VERSION 5.7 ;
  NAMESCASESENSITIVE ON ;
  NOWIREEXTENSIONATPIN ON ;
  DIVIDERCHAR "/" ;
  BUSBITCHARS "[]" ;
UNITS
  DATABASE MICRONS 200 ;
END UNITS

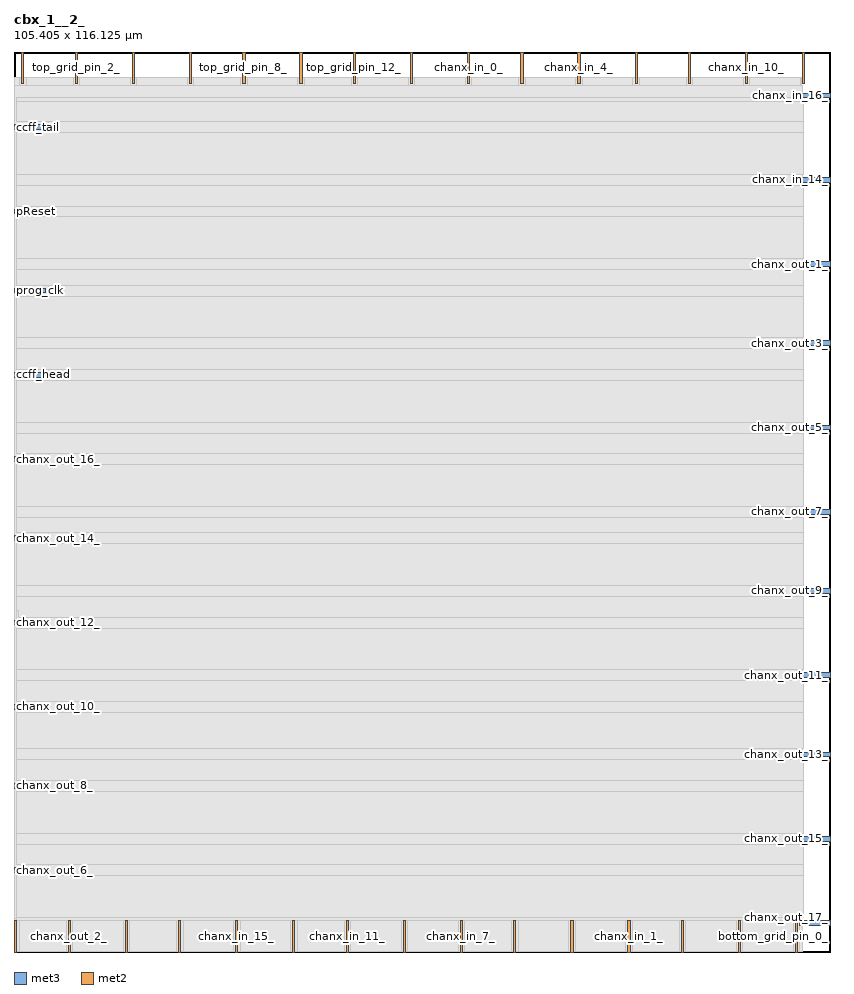
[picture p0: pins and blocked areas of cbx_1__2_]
MACRO cbx_1__2_
  CLASS BLOCK ;
  FOREIGN cbx_1__2_ ;
  ORIGIN 0.000 0.000 ;
  SIZE 105.405 BY 116.125 ;
  PIN chanx_out_8_
    DIRECTION OUTPUT TRISTATE ;
    PORT
      LAYER met3 ;
        RECT 0.000 21.120 4.000 21.720 ;
    END
  END chanx_out_8_
  PIN top_grid_pin_0_
    DIRECTION OUTPUT TRISTATE ;
    PORT
      LAYER met2 ;
        RECT 1.010 112.125 1.290 116.125 ;
    END
  END top_grid_pin_0_
  PIN pReset
    DIRECTION INPUT ;
    PORT
      LAYER met3 ;
        RECT 0.000 95.240 4.000 95.840 ;
    END
  END pReset
  PIN chanx_out_16_
    DIRECTION OUTPUT TRISTATE ;
    PORT
      LAYER met3 ;
        RECT 0.000 63.280 4.000 63.880 ;
    END
  END chanx_out_16_
  PIN top_grid_pin_12_
    DIRECTION OUTPUT TRISTATE ;
    PORT
      LAYER met2 ;
        RECT 43.790 112.125 44.070 116.125 ;
    END
  END top_grid_pin_12_
  PIN chanx_in_5_
    DIRECTION INPUT ;
    PORT
      LAYER met2 ;
        RECT 64.490 0.000 64.770 4.000 ;
    END
  END chanx_in_5_
  PIN chanx_in_1_
    DIRECTION INPUT ;
    PORT
      LAYER met2 ;
        RECT 79.210 0.000 79.490 4.000 ;
    END
  END chanx_in_1_
  PIN top_grid_pin_8_
    DIRECTION OUTPUT TRISTATE ;
    PORT
      LAYER met2 ;
        RECT 29.530 112.125 29.810 116.125 ;
    END
  END top_grid_pin_8_
  PIN chanx_out_10_
    DIRECTION OUTPUT TRISTATE ;
    PORT
      LAYER met3 ;
        RECT 0.000 31.320 4.000 31.920 ;
    END
  END chanx_out_10_
  PIN chanx_in_10_
    DIRECTION INPUT ;
    PORT
      LAYER met2 ;
        RECT 94.390 112.125 94.670 116.125 ;
    END
  END chanx_in_10_
  PIN chanx_out_3_
    DIRECTION OUTPUT TRISTATE ;
    PORT
      LAYER met3 ;
        RECT 101.405 78.240 105.405 78.840 ;
    END
  END chanx_out_3_
  PIN prog_clk
    DIRECTION INPUT ;
    PORT
      LAYER met3 ;
        RECT 0.000 85.040 4.000 85.640 ;
    END
  END prog_clk
  PIN bottom_grid_pin_8_
    DIRECTION OUTPUT TRISTATE ;
    PORT
      LAYER met2 ;
        RECT 86.110 0.000 86.390 4.000 ;
    END
  END bottom_grid_pin_8_
  PIN ccff_tail
    DIRECTION OUTPUT TRISTATE ;
    PORT
      LAYER met3 ;
        RECT 0.000 106.120 4.000 106.720 ;
    END
  END ccff_tail
  PIN top_grid_pin_14_
    DIRECTION OUTPUT TRISTATE ;
    PORT
      LAYER met2 ;
        RECT 51.150 112.125 51.430 116.125 ;
    END
  END top_grid_pin_14_
  PIN chanx_out_0_
    DIRECTION OUTPUT TRISTATE ;
    PORT
      LAYER met2 ;
        RECT 14.350 0.000 14.630 4.000 ;
    END
  END chanx_out_0_
  PIN chanx_out_13_
    DIRECTION OUTPUT TRISTATE ;
    PORT
      LAYER met3 ;
        RECT 101.405 25.200 105.405 25.800 ;
    END
  END chanx_out_13_
  PIN chanx_out_12_
    DIRECTION OUTPUT TRISTATE ;
    PORT
      LAYER met3 ;
        RECT 0.000 42.200 4.000 42.800 ;
    END
  END chanx_out_12_
  PIN chanx_out_9_
    DIRECTION OUTPUT TRISTATE ;
    PORT
      LAYER met3 ;
        RECT 101.405 46.280 105.405 46.880 ;
    END
  END chanx_out_9_
  PIN chanx_in_16_
    DIRECTION INPUT ;
    PORT
      LAYER met3 ;
        RECT 101.405 110.200 105.405 110.800 ;
    END
  END chanx_in_16_
  PIN chanx_out_15_
    DIRECTION OUTPUT TRISTATE ;
    PORT
      LAYER met3 ;
        RECT 101.405 14.320 105.405 14.920 ;
    END
  END chanx_out_15_
  PIN top_grid_pin_2_
    DIRECTION OUTPUT TRISTATE ;
    PORT
      LAYER met2 ;
        RECT 7.910 112.125 8.190 116.125 ;
    END
  END top_grid_pin_2_
  PIN chanx_in_4_
    DIRECTION INPUT ;
    PORT
      LAYER met2 ;
        RECT 72.770 112.125 73.050 116.125 ;
    END
  END chanx_in_4_
  PIN chanx_out_17_
    DIRECTION OUTPUT TRISTATE ;
    PORT
      LAYER met3 ;
        RECT 101.405 3.440 105.405 4.040 ;
    END
  END chanx_out_17_
  PIN top_grid_pin_10_
    DIRECTION OUTPUT TRISTATE ;
    PORT
      LAYER met2 ;
        RECT 36.890 112.125 37.170 116.125 ;
    END
  END top_grid_pin_10_
  PIN chanx_in_13_
    DIRECTION INPUT ;
    PORT
      LAYER met2 ;
        RECT 35.970 0.000 36.250 4.000 ;
    END
  END chanx_in_13_
  PIN top_grid_pin_6_
    DIRECTION OUTPUT TRISTATE ;
    PORT
      LAYER met2 ;
        RECT 22.630 112.125 22.910 116.125 ;
    END
  END top_grid_pin_6_
  PIN bottom_grid_pin_0_
    DIRECTION OUTPUT TRISTATE ;
    PORT
      LAYER met2 ;
        RECT 100.830 0.000 101.110 4.000 ;
    END
  END bottom_grid_pin_0_
  PIN chanx_in_8_
    DIRECTION INPUT ;
    PORT
      LAYER met2 ;
        RECT 87.030 112.125 87.310 116.125 ;
    END
  END chanx_in_8_
  PIN ccff_head
    DIRECTION INPUT ;
    PORT
      LAYER met3 ;
        RECT 0.000 74.160 4.000 74.760 ;
    END
  END ccff_head
  PIN chanx_in_9_
    DIRECTION INPUT ;
    PORT
      LAYER met2 ;
        RECT 50.230 0.000 50.510 4.000 ;
    END
  END chanx_in_9_
  PIN chanx_out_1_
    DIRECTION OUTPUT TRISTATE ;
    PORT
      LAYER met3 ;
        RECT 101.405 88.440 105.405 89.040 ;
    END
  END chanx_out_1_
  PIN chanx_in_6_
    DIRECTION INPUT ;
    PORT
      LAYER met2 ;
        RECT 80.130 112.125 80.410 116.125 ;
    END
  END chanx_in_6_
  PIN chanx_in_12_
    DIRECTION INPUT ;
    PORT
      LAYER met2 ;
        RECT 101.750 112.125 102.030 116.125 ;
    END
  END chanx_in_12_
  PIN chanx_out_11_
    DIRECTION OUTPUT TRISTATE ;
    PORT
      LAYER met3 ;
        RECT 101.405 35.400 105.405 36.000 ;
    END
  END chanx_out_11_
  PIN chanx_in_15_
    DIRECTION INPUT ;
    PORT
      LAYER met2 ;
        RECT 28.610 0.000 28.890 4.000 ;
    END
  END chanx_in_15_
  PIN chanx_in_17_
    DIRECTION INPUT ;
    PORT
      LAYER met2 ;
        RECT 21.250 0.000 21.530 4.000 ;
    END
  END chanx_in_17_
  PIN bottom_grid_pin_4_
    DIRECTION OUTPUT TRISTATE ;
    PORT
      LAYER met2 ;
        RECT 93.470 0.000 93.750 4.000 ;
    END
  END bottom_grid_pin_4_
  PIN chanx_in_3_
    DIRECTION INPUT ;
    PORT
      LAYER met2 ;
        RECT 71.850 0.000 72.130 4.000 ;
    END
  END chanx_in_3_
  PIN chanx_in_7_
    DIRECTION INPUT ;
    PORT
      LAYER met2 ;
        RECT 57.590 0.000 57.870 4.000 ;
    END
  END chanx_in_7_
  PIN chanx_in_11_
    DIRECTION INPUT ;
    PORT
      LAYER met2 ;
        RECT 42.870 0.000 43.150 4.000 ;
    END
  END chanx_in_11_
  PIN chanx_out_14_
    DIRECTION OUTPUT TRISTATE ;
    PORT
      LAYER met3 ;
        RECT 0.000 53.080 4.000 53.680 ;
    END
  END chanx_out_14_
  PIN chanx_out_2_
    DIRECTION OUTPUT TRISTATE ;
    PORT
      LAYER met2 ;
        RECT 6.990 0.000 7.270 4.000 ;
    END
  END chanx_out_2_
  PIN chanx_in_0_
    DIRECTION INPUT ;
    PORT
      LAYER met2 ;
        RECT 58.510 112.125 58.790 116.125 ;
    END
  END chanx_in_0_
  PIN chanx_out_5_
    DIRECTION OUTPUT TRISTATE ;
    PORT
      LAYER met3 ;
        RECT 101.405 67.360 105.405 67.960 ;
    END
  END chanx_out_5_
  PIN chanx_out_6_
    DIRECTION OUTPUT TRISTATE ;
    PORT
      LAYER met3 ;
        RECT 0.000 10.240 4.000 10.840 ;
    END
  END chanx_out_6_
  PIN top_grid_pin_4_
    DIRECTION OUTPUT TRISTATE ;
    PORT
      LAYER met2 ;
        RECT 15.270 112.125 15.550 116.125 ;
    END
  END top_grid_pin_4_
  PIN chanx_in_2_
    DIRECTION INPUT ;
    PORT
      LAYER met2 ;
        RECT 65.410 112.125 65.690 116.125 ;
    END
  END chanx_in_2_
  PIN chanx_in_14_
    DIRECTION INPUT ;
    PORT
      LAYER met3 ;
        RECT 101.405 99.320 105.405 99.920 ;
    END
  END chanx_in_14_
  PIN chanx_out_7_
    DIRECTION OUTPUT TRISTATE ;
    PORT
      LAYER met3 ;
        RECT 101.405 56.480 105.405 57.080 ;
    END
  END chanx_out_7_
  PIN chanx_out_4_
    DIRECTION OUTPUT TRISTATE ;
    PORT
      LAYER met2 ;
        RECT 0.090 0.000 0.370 4.000 ;
    END
  END chanx_out_4_
  OBS
      LAYER li1 ;
        RECT 5.520 10.795 99.820 103.445 ;
      LAYER met1 ;
        RECT 0.070 0.040 101.590 112.840 ;
      LAYER met2 ;
        RECT 0.090 111.845 0.730 112.870 ;
        RECT 1.570 111.845 7.630 112.870 ;
        RECT 8.470 111.845 14.990 112.870 ;
        RECT 15.830 111.845 22.350 112.870 ;
        RECT 23.190 111.845 29.250 112.870 ;
        RECT 30.090 111.845 36.610 112.870 ;
        RECT 37.450 111.845 43.510 112.870 ;
        RECT 44.350 111.845 50.870 112.870 ;
        RECT 51.710 111.845 58.230 112.870 ;
        RECT 59.070 111.845 65.130 112.870 ;
        RECT 65.970 111.845 72.490 112.870 ;
        RECT 73.330 111.845 79.850 112.870 ;
        RECT 80.690 111.845 86.750 112.870 ;
        RECT 87.590 111.845 94.110 112.870 ;
        RECT 94.950 111.845 101.470 112.870 ;
        RECT 0.090 4.280 101.750 111.845 ;
        RECT 0.650 0.010 6.710 4.280 ;
        RECT 7.550 0.010 14.070 4.280 ;
        RECT 14.910 0.010 20.970 4.280 ;
        RECT 21.810 0.010 28.330 4.280 ;
        RECT 29.170 0.010 35.690 4.280 ;
        RECT 36.530 0.010 42.590 4.280 ;
        RECT 43.430 0.010 49.950 4.280 ;
        RECT 50.790 0.010 57.310 4.280 ;
        RECT 58.150 0.010 64.210 4.280 ;
        RECT 65.050 0.010 71.570 4.280 ;
        RECT 72.410 0.010 78.930 4.280 ;
        RECT 79.770 0.010 85.830 4.280 ;
        RECT 86.670 0.010 93.190 4.280 ;
        RECT 94.030 0.010 100.550 4.280 ;
        RECT 101.390 0.010 101.750 4.280 ;
      LAYER met3 ;
        RECT 0.270 109.800 101.005 110.200 ;
        RECT 0.270 107.120 101.810 109.800 ;
        RECT 4.400 105.720 101.810 107.120 ;
        RECT 0.270 100.320 101.810 105.720 ;
        RECT 0.270 98.920 101.005 100.320 ;
        RECT 0.270 96.240 101.810 98.920 ;
        RECT 4.400 94.840 101.810 96.240 ;
        RECT 0.270 89.440 101.810 94.840 ;
        RECT 0.270 88.040 101.005 89.440 ;
        RECT 0.270 86.040 101.810 88.040 ;
        RECT 4.400 84.640 101.810 86.040 ;
        RECT 0.270 79.240 101.810 84.640 ;
        RECT 0.270 77.840 101.005 79.240 ;
        RECT 0.270 75.160 101.810 77.840 ;
        RECT 4.400 73.760 101.810 75.160 ;
        RECT 0.270 68.360 101.810 73.760 ;
        RECT 0.270 66.960 101.005 68.360 ;
        RECT 0.270 64.280 101.810 66.960 ;
        RECT 4.400 62.880 101.810 64.280 ;
        RECT 0.270 57.480 101.810 62.880 ;
        RECT 0.270 56.080 101.005 57.480 ;
        RECT 0.270 54.080 101.810 56.080 ;
        RECT 4.400 52.680 101.810 54.080 ;
        RECT 0.270 47.280 101.810 52.680 ;
        RECT 0.270 45.880 101.005 47.280 ;
        RECT 0.270 43.200 101.810 45.880 ;
        RECT 4.400 41.800 101.810 43.200 ;
        RECT 0.270 36.400 101.810 41.800 ;
        RECT 0.270 35.000 101.005 36.400 ;
        RECT 0.270 32.320 101.810 35.000 ;
        RECT 4.400 30.920 101.810 32.320 ;
        RECT 0.270 26.200 101.810 30.920 ;
        RECT 0.270 24.800 101.005 26.200 ;
        RECT 0.270 22.120 101.810 24.800 ;
        RECT 4.400 20.720 101.810 22.120 ;
        RECT 0.270 15.320 101.810 20.720 ;
        RECT 0.270 13.920 101.005 15.320 ;
        RECT 0.270 11.240 101.810 13.920 ;
        RECT 4.400 9.840 101.810 11.240 ;
        RECT 0.270 4.440 101.810 9.840 ;
        RECT 0.270 4.040 101.005 4.440 ;
      LAYER met4 ;
        RECT 0.295 42.335 0.625 44.025 ;
  END
END cbx_1__2_
END LIBRARY

